VERSION 5.7 ;
  NOWIREEXTENSIONATPIN ON ;
  DIVIDERCHAR "/" ;
  BUSBITCHARS "[]" ;
MACRO INV_B_13409687_0_1653520173
  CLASS BLOCK ;
  FOREIGN INV_B_13409687_0_1653520173 ;
  ORIGIN 0.000 0.000 ;
  SIZE 5.415 BY 7.560 ;
  OBS
      LAYER nwell ;
        RECT 0.000 0.000 3.440 7.560 ;
      LAYER pwell ;
        RECT 4.515 6.030 4.945 7.410 ;
        RECT 4.045 2.495 5.415 3.175 ;
      LAYER li1 ;
        RECT 1.165 6.215 1.415 7.225 ;
        RECT 2.025 6.215 2.275 7.225 ;
        RECT 4.605 6.215 4.855 7.225 ;
        RECT 1.165 4.115 1.415 5.125 ;
        RECT 2.025 4.115 2.275 5.125 ;
        RECT 4.605 4.115 4.855 5.125 ;
        RECT 0.735 0.335 0.985 3.865 ;
        RECT 1.165 0.335 1.415 3.865 ;
        RECT 1.595 0.335 1.845 3.865 ;
        RECT 2.025 0.335 2.275 3.865 ;
        RECT 2.455 0.335 2.705 3.865 ;
        RECT 4.175 0.335 4.425 3.865 ;
        RECT 4.605 0.335 4.855 3.865 ;
        RECT 5.035 0.335 5.285 3.865 ;
      LAYER mcon ;
        RECT 1.205 6.635 1.375 6.805 ;
        RECT 2.065 6.635 2.235 6.805 ;
        RECT 4.645 6.635 4.815 6.805 ;
        RECT 1.205 4.535 1.375 4.705 ;
        RECT 2.065 4.535 2.235 4.705 ;
        RECT 4.645 4.535 4.815 4.705 ;
        RECT 0.775 0.755 0.945 0.925 ;
        RECT 1.205 0.335 1.375 0.505 ;
        RECT 1.635 0.755 1.805 0.925 ;
        RECT 2.065 0.335 2.235 0.505 ;
        RECT 2.495 0.755 2.665 0.925 ;
        RECT 4.215 0.755 4.385 0.925 ;
        RECT 4.645 0.335 4.815 0.505 ;
        RECT 5.075 0.755 5.245 0.925 ;
      LAYER met1 ;
        RECT 1.120 6.580 2.320 6.860 ;
        RECT 4.130 6.580 5.330 6.860 ;
        RECT 1.120 4.480 4.900 4.760 ;
        RECT 0.690 0.700 2.750 0.980 ;
        RECT 4.130 0.700 5.330 0.980 ;
        RECT 1.120 0.280 4.900 0.560 ;
      LAYER via ;
        RECT 5.030 6.590 5.290 6.850 ;
        RECT 5.030 0.710 5.290 0.970 ;
      LAYER met2 ;
        RECT 5.020 0.680 5.300 6.880 ;
  END
END INV_B_13409687_0_1653520173
MACRO NMOS_S_22639876_X1_Y1_1653520174
  CLASS BLOCK ;
  FOREIGN NMOS_S_22639876_X1_Y1_1653520174 ;
  ORIGIN -0.260 -0.280 ;
  SIZE 1.715 BY 7.130 ;
  OBS
      LAYER pwell ;
        RECT 1.075 6.030 1.505 7.410 ;
        RECT 0.605 2.495 1.975 3.175 ;
      LAYER li1 ;
        RECT 1.165 6.215 1.415 7.225 ;
        RECT 1.165 4.115 1.415 5.125 ;
        RECT 0.735 0.335 0.985 3.865 ;
        RECT 1.165 0.335 1.415 3.865 ;
        RECT 1.595 0.335 1.845 3.865 ;
      LAYER mcon ;
        RECT 1.205 6.635 1.375 6.805 ;
        RECT 1.205 4.535 1.375 4.705 ;
        RECT 0.775 0.755 0.945 0.925 ;
        RECT 1.205 0.335 1.375 0.505 ;
        RECT 1.635 0.755 1.805 0.925 ;
      LAYER met1 ;
        RECT 0.690 6.580 1.890 6.860 ;
        RECT 0.260 4.480 1.460 4.760 ;
        RECT 0.690 0.700 1.890 0.980 ;
        RECT 0.260 0.280 1.460 0.560 ;
      LAYER via ;
        RECT 1.590 6.590 1.850 6.850 ;
        RECT 1.590 0.710 1.850 0.970 ;
      LAYER met2 ;
        RECT 1.580 0.680 1.860 6.880 ;
  END
END NMOS_S_22639876_X1_Y1_1653520174
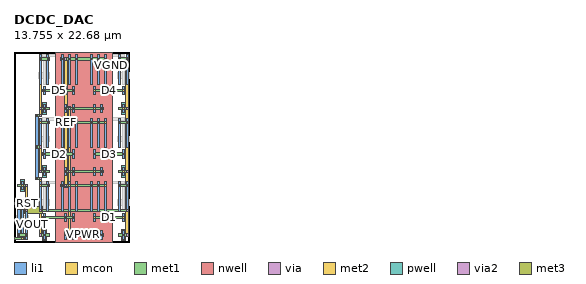
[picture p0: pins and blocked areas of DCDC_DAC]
MACRO DCDC_DAC
  CLASS BLOCK ;
  FOREIGN DCDC_DAC ;
  ORIGIN -0.260 0.000 ;
  SIZE 13.755 BY 22.680 ;
  PIN D0
    ANTENNAGATEAREA 0.378000 ;
    PORT
      LAYER li1 ;
        RECT 3.745 2.435 3.995 3.445 ;
        RECT 6.325 2.435 6.575 3.445 ;
        RECT 7.185 2.435 7.435 3.445 ;
      LAYER mcon ;
        RECT 3.785 2.855 3.955 3.025 ;
        RECT 6.365 2.855 6.535 3.025 ;
        RECT 7.225 2.855 7.395 3.025 ;
      LAYER met1 ;
        RECT 3.700 2.800 7.480 3.080 ;
    END
  END D0
  PIN VPWR
    USE POWER ;
    PORT
      LAYER nwell ;
        RECT 5.160 0.000 12.040 22.680 ;
      LAYER li1 ;
        RECT 6.325 15.455 6.575 16.465 ;
        RECT 7.185 15.455 7.435 16.465 ;
        RECT 9.765 15.455 10.015 16.465 ;
        RECT 10.625 15.455 10.875 16.465 ;
        RECT 6.325 7.895 6.575 8.905 ;
        RECT 7.185 7.895 7.435 8.905 ;
        RECT 9.765 7.895 10.015 8.905 ;
        RECT 10.625 7.895 10.875 8.905 ;
        RECT 6.325 0.335 6.575 1.345 ;
        RECT 7.185 0.335 7.435 1.345 ;
        RECT 9.765 0.335 10.015 1.345 ;
        RECT 10.625 0.335 10.875 1.345 ;
      LAYER mcon ;
        RECT 6.365 15.875 6.535 16.045 ;
        RECT 7.225 15.875 7.395 16.045 ;
        RECT 9.805 15.875 9.975 16.045 ;
        RECT 10.665 15.875 10.835 16.045 ;
        RECT 6.365 8.315 6.535 8.485 ;
        RECT 7.225 8.315 7.395 8.485 ;
        RECT 9.805 8.315 9.975 8.485 ;
        RECT 10.665 8.315 10.835 8.485 ;
        RECT 6.365 0.755 6.535 0.925 ;
        RECT 7.225 0.755 7.395 0.925 ;
        RECT 9.805 0.755 9.975 0.925 ;
        RECT 10.665 0.755 10.835 0.925 ;
      LAYER met1 ;
        RECT 6.280 15.820 10.920 16.100 ;
        RECT 6.280 8.260 10.920 8.540 ;
        RECT 6.280 0.700 10.920 0.980 ;
      LAYER via ;
        RECT 6.750 15.830 7.010 16.090 ;
        RECT 6.750 8.270 7.010 8.530 ;
        RECT 6.750 0.710 7.010 0.970 ;
      LAYER met2 ;
        RECT 6.740 0.680 7.020 16.120 ;
    END
  END VPWR
  PIN REF
    ANTENNADIFFAREA 2.041200 ;
    PORT
      LAYER li1 ;
        RECT 5.895 18.815 6.145 22.345 ;
        RECT 6.755 18.815 7.005 22.345 ;
        RECT 7.615 18.815 7.865 22.345 ;
        RECT 9.335 18.815 9.585 22.345 ;
        RECT 10.195 18.815 10.445 22.345 ;
        RECT 11.055 18.815 11.305 22.345 ;
        RECT 5.895 11.255 6.145 14.785 ;
        RECT 6.755 11.255 7.005 14.785 ;
        RECT 7.615 11.255 7.865 14.785 ;
        RECT 9.335 11.255 9.585 14.785 ;
        RECT 10.195 11.255 10.445 14.785 ;
        RECT 11.055 11.255 11.305 14.785 ;
        RECT 5.895 3.695 6.145 7.225 ;
        RECT 6.755 3.695 7.005 7.225 ;
        RECT 7.615 3.695 7.865 7.225 ;
        RECT 9.335 3.695 9.585 7.225 ;
        RECT 10.195 3.695 10.445 7.225 ;
        RECT 11.055 3.695 11.305 7.225 ;
      LAYER mcon ;
        RECT 5.935 21.755 6.105 21.925 ;
        RECT 6.795 21.755 6.965 21.925 ;
        RECT 7.655 21.755 7.825 21.925 ;
        RECT 9.375 21.755 9.545 21.925 ;
        RECT 10.235 21.755 10.405 21.925 ;
        RECT 11.095 21.755 11.265 21.925 ;
        RECT 5.935 14.195 6.105 14.365 ;
        RECT 6.795 14.195 6.965 14.365 ;
        RECT 7.655 14.195 7.825 14.365 ;
        RECT 9.375 14.195 9.545 14.365 ;
        RECT 10.235 14.195 10.405 14.365 ;
        RECT 11.095 14.195 11.265 14.365 ;
        RECT 5.935 6.635 6.105 6.805 ;
        RECT 6.795 6.635 6.965 6.805 ;
        RECT 7.655 6.635 7.825 6.805 ;
        RECT 9.375 6.635 9.545 6.805 ;
        RECT 10.235 6.635 10.405 6.805 ;
        RECT 11.095 6.635 11.265 6.805 ;
      LAYER met1 ;
        RECT 5.850 21.700 11.350 21.980 ;
        RECT 5.850 14.140 11.350 14.420 ;
        RECT 5.850 6.580 11.350 6.860 ;
      LAYER via ;
        RECT 6.320 21.710 6.580 21.970 ;
        RECT 6.320 14.150 6.580 14.410 ;
        RECT 6.320 6.590 6.580 6.850 ;
      LAYER met2 ;
        RECT 6.310 6.560 6.590 22.000 ;
    END
  END REF
  PIN D5
    ANTENNAGATEAREA 0.378000 ;
    PORT
      LAYER li1 ;
        RECT 3.745 17.555 3.995 18.565 ;
        RECT 6.325 17.555 6.575 18.565 ;
        RECT 7.185 17.555 7.435 18.565 ;
      LAYER mcon ;
        RECT 3.785 17.975 3.955 18.145 ;
        RECT 6.365 17.975 6.535 18.145 ;
        RECT 7.225 17.975 7.395 18.145 ;
      LAYER met1 ;
        RECT 3.700 17.920 7.480 18.200 ;
    END
  END D5
  PIN D1
    ANTENNAGATEAREA 0.378000 ;
    PORT
      LAYER li1 ;
        RECT 9.765 2.435 10.015 3.445 ;
        RECT 10.625 2.435 10.875 3.445 ;
        RECT 13.205 2.435 13.455 3.445 ;
      LAYER mcon ;
        RECT 9.805 2.855 9.975 3.025 ;
        RECT 10.665 2.855 10.835 3.025 ;
        RECT 13.245 2.855 13.415 3.025 ;
      LAYER met1 ;
        RECT 9.720 2.800 13.500 3.080 ;
    END
  END D1
  PIN D2
    ANTENNAGATEAREA 0.378000 ;
    PORT
      LAYER li1 ;
        RECT 3.745 9.995 3.995 11.005 ;
        RECT 6.325 9.995 6.575 11.005 ;
        RECT 7.185 9.995 7.435 11.005 ;
      LAYER mcon ;
        RECT 3.785 10.415 3.955 10.585 ;
        RECT 6.365 10.415 6.535 10.585 ;
        RECT 7.225 10.415 7.395 10.585 ;
      LAYER met1 ;
        RECT 3.700 10.360 7.480 10.640 ;
    END
  END D2
  PIN D3
    ANTENNAGATEAREA 0.378000 ;
    PORT
      LAYER li1 ;
        RECT 9.765 9.995 10.015 11.005 ;
        RECT 10.625 9.995 10.875 11.005 ;
        RECT 13.205 9.995 13.455 11.005 ;
      LAYER mcon ;
        RECT 9.805 10.415 9.975 10.585 ;
        RECT 10.665 10.415 10.835 10.585 ;
        RECT 13.245 10.415 13.415 10.585 ;
      LAYER met1 ;
        RECT 9.720 10.360 13.500 10.640 ;
    END
  END D3
  PIN D4
    ANTENNAGATEAREA 0.378000 ;
    PORT
      LAYER li1 ;
        RECT 9.765 17.555 10.015 18.565 ;
        RECT 10.625 17.555 10.875 18.565 ;
        RECT 13.205 17.555 13.455 18.565 ;
      LAYER mcon ;
        RECT 9.805 17.975 9.975 18.145 ;
        RECT 10.665 17.975 10.835 18.145 ;
        RECT 13.245 17.975 13.415 18.145 ;
      LAYER met1 ;
        RECT 9.720 17.920 13.500 18.200 ;
    END
  END D4
  PIN VOUT
    ANTENNADIFFAREA 0.117600 ;
    PORT
      LAYER li1 ;
        RECT 1.165 0.335 1.415 3.865 ;
      LAYER mcon ;
        RECT 1.205 0.335 1.375 0.505 ;
      LAYER met1 ;
        RECT 0.260 0.280 1.460 0.560 ;
    END
  END VOUT
  PIN RST
    ANTENNAGATEAREA 0.126000 ;
    PORT
      LAYER li1 ;
        RECT 1.165 4.115 1.415 5.125 ;
      LAYER mcon ;
        RECT 1.205 4.535 1.375 4.705 ;
      LAYER met1 ;
        RECT 0.260 4.480 1.460 4.760 ;
    END
  END RST
  PIN VGND
    USE GROUND ;
    PORT
      LAYER pwell ;
        RECT 3.655 15.270 4.085 16.650 ;
        RECT 13.115 15.270 13.545 16.650 ;
        RECT 3.655 7.710 4.085 9.090 ;
        RECT 13.115 7.710 13.545 9.090 ;
        RECT 1.075 6.030 1.505 7.410 ;
        RECT 3.655 0.150 4.085 1.530 ;
        RECT 13.115 0.150 13.545 1.530 ;
      LAYER li1 ;
        RECT 3.315 18.815 3.565 22.345 ;
        RECT 4.175 18.815 4.425 22.345 ;
        RECT 12.775 18.815 13.025 22.345 ;
        RECT 13.635 18.815 13.885 22.345 ;
        RECT 3.745 15.455 3.995 16.465 ;
        RECT 13.205 15.455 13.455 16.465 ;
        RECT 2.885 7.475 3.135 15.205 ;
        RECT 3.315 11.255 3.565 14.785 ;
        RECT 4.175 11.255 4.425 14.785 ;
        RECT 12.775 11.255 13.025 14.785 ;
        RECT 13.635 11.255 13.885 14.785 ;
        RECT 3.745 7.895 3.995 8.905 ;
        RECT 13.205 7.895 13.455 8.905 ;
        RECT 1.165 6.215 1.415 7.225 ;
        RECT 0.735 0.335 0.985 3.865 ;
        RECT 1.595 0.335 1.845 3.865 ;
        RECT 3.315 3.695 3.565 7.225 ;
        RECT 4.175 3.695 4.425 7.225 ;
        RECT 12.775 3.695 13.025 7.225 ;
        RECT 13.635 3.695 13.885 7.225 ;
        RECT 3.745 0.335 3.995 1.345 ;
        RECT 13.205 0.335 13.455 1.345 ;
      LAYER mcon ;
        RECT 3.355 21.755 3.525 21.925 ;
        RECT 4.215 21.755 4.385 21.925 ;
        RECT 12.815 21.755 12.985 21.925 ;
        RECT 13.675 21.755 13.845 21.925 ;
        RECT 3.785 15.875 3.955 16.045 ;
        RECT 13.245 15.875 13.415 16.045 ;
        RECT 2.925 15.035 3.095 15.205 ;
        RECT 2.925 11.255 3.095 11.425 ;
        RECT 3.355 14.195 3.525 14.365 ;
        RECT 4.215 14.195 4.385 14.365 ;
        RECT 12.815 14.195 12.985 14.365 ;
        RECT 13.675 14.195 13.845 14.365 ;
        RECT 3.785 8.315 3.955 8.485 ;
        RECT 13.245 8.315 13.415 8.485 ;
        RECT 2.925 7.475 3.095 7.645 ;
        RECT 1.205 6.635 1.375 6.805 ;
        RECT 3.355 6.635 3.525 6.805 ;
        RECT 0.775 0.755 0.945 0.925 ;
        RECT 4.215 6.635 4.385 6.805 ;
        RECT 12.815 6.635 12.985 6.805 ;
        RECT 13.675 6.635 13.845 6.805 ;
        RECT 1.635 0.755 1.805 0.925 ;
        RECT 3.785 0.755 3.955 0.925 ;
        RECT 13.245 0.755 13.415 0.925 ;
      LAYER met1 ;
        RECT 3.270 21.700 4.470 21.980 ;
        RECT 12.730 21.700 13.930 21.980 ;
        RECT 3.270 15.820 4.470 16.100 ;
        RECT 12.730 15.820 13.930 16.100 ;
        RECT 2.840 14.980 3.600 15.260 ;
        RECT 3.270 14.140 4.470 14.420 ;
        RECT 12.730 14.140 13.930 14.420 ;
        RECT 2.840 11.200 3.600 11.480 ;
        RECT 3.270 8.260 4.470 8.540 ;
        RECT 12.730 8.260 13.930 8.540 ;
        RECT 2.840 7.420 3.600 7.700 ;
        RECT 0.690 6.580 1.890 6.860 ;
        RECT 3.270 6.580 4.470 6.860 ;
        RECT 12.730 6.580 13.930 6.860 ;
        RECT 3.280 3.640 13.920 3.920 ;
        RECT 0.690 0.700 1.890 0.980 ;
        RECT 3.270 0.700 4.470 0.980 ;
        RECT 12.730 0.700 13.930 0.980 ;
      LAYER via ;
        RECT 3.310 21.710 3.570 21.970 ;
        RECT 13.630 21.710 13.890 21.970 ;
        RECT 3.310 15.830 3.570 16.090 ;
        RECT 13.630 15.830 13.890 16.090 ;
        RECT 3.310 14.990 3.570 15.250 ;
        RECT 3.310 14.150 3.570 14.410 ;
        RECT 13.630 14.150 13.890 14.410 ;
        RECT 3.310 11.210 3.570 11.470 ;
        RECT 3.310 8.270 3.570 8.530 ;
        RECT 13.630 8.270 13.890 8.530 ;
        RECT 3.310 7.430 3.570 7.690 ;
        RECT 1.590 6.590 1.850 6.850 ;
        RECT 3.310 6.590 3.570 6.850 ;
        RECT 13.630 6.590 13.890 6.850 ;
        RECT 3.310 3.650 3.570 3.910 ;
        RECT 13.630 3.650 13.890 3.910 ;
        RECT 1.590 0.710 1.850 0.970 ;
        RECT 3.310 0.710 3.570 0.970 ;
        RECT 13.630 0.710 13.890 0.970 ;
      LAYER met2 ;
        RECT 3.300 14.960 3.580 22.000 ;
        RECT 3.300 8.240 3.580 14.440 ;
        RECT 1.580 0.680 1.860 6.880 ;
        RECT 3.300 0.680 3.580 7.720 ;
        RECT 13.620 0.680 13.900 22.000 ;
      LAYER via2 ;
        RECT 1.580 3.640 1.860 3.920 ;
        RECT 3.300 3.640 3.580 3.920 ;
      LAYER met3 ;
        RECT 1.555 3.380 3.605 4.180 ;
    END
  END VGND
  OBS
      LAYER pwell ;
        RECT 3.185 19.505 4.555 20.185 ;
        RECT 12.645 19.505 14.015 20.185 ;
        RECT 3.185 11.945 4.555 12.625 ;
        RECT 12.645 11.945 14.015 12.625 ;
        RECT 3.185 4.385 4.555 5.065 ;
        RECT 12.645 4.385 14.015 5.065 ;
        RECT 0.605 2.495 1.975 3.175 ;
      LAYER li1 ;
        RECT 3.745 18.815 3.995 22.345 ;
        RECT 6.325 18.815 6.575 22.345 ;
        RECT 7.185 18.815 7.435 22.345 ;
        RECT 9.765 18.815 10.015 22.345 ;
        RECT 10.625 18.815 10.875 22.345 ;
        RECT 13.205 18.815 13.455 22.345 ;
        RECT 3.745 11.255 3.995 14.785 ;
        RECT 6.325 11.255 6.575 14.785 ;
        RECT 7.185 11.255 7.435 14.785 ;
        RECT 9.765 11.255 10.015 14.785 ;
        RECT 10.625 11.255 10.875 14.785 ;
        RECT 13.205 11.255 13.455 14.785 ;
        RECT 3.745 3.695 3.995 7.225 ;
        RECT 6.325 3.695 6.575 7.225 ;
        RECT 7.185 3.695 7.435 7.225 ;
        RECT 9.765 3.695 10.015 7.225 ;
        RECT 10.625 3.695 10.875 7.225 ;
        RECT 13.205 3.695 13.455 7.225 ;
      LAYER mcon ;
        RECT 3.785 22.175 3.955 22.345 ;
        RECT 6.365 22.175 6.535 22.345 ;
        RECT 7.225 22.175 7.395 22.345 ;
        RECT 9.805 22.175 9.975 22.345 ;
        RECT 10.665 22.175 10.835 22.345 ;
        RECT 13.245 22.175 13.415 22.345 ;
        RECT 3.785 14.615 3.955 14.785 ;
        RECT 6.365 14.615 6.535 14.785 ;
        RECT 7.225 14.615 7.395 14.785 ;
        RECT 9.805 14.615 9.975 14.785 ;
        RECT 10.665 14.615 10.835 14.785 ;
        RECT 13.245 14.615 13.415 14.785 ;
        RECT 3.785 7.055 3.955 7.225 ;
        RECT 6.365 7.055 6.535 7.225 ;
        RECT 7.225 7.055 7.395 7.225 ;
        RECT 9.805 7.055 9.975 7.225 ;
        RECT 10.665 7.055 10.835 7.225 ;
        RECT 13.245 7.055 13.415 7.225 ;
      LAYER met1 ;
        RECT 3.700 22.120 7.480 22.400 ;
        RECT 9.720 22.120 13.500 22.400 ;
        RECT 3.700 14.560 7.480 14.840 ;
        RECT 9.720 14.560 13.500 14.840 ;
        RECT 3.700 7.000 7.480 7.280 ;
        RECT 9.720 7.000 13.500 7.280 ;
  END
END DCDC_DAC
END LIBRARY
